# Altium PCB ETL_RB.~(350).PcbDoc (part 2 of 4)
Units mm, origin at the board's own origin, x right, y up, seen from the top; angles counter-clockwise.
Board outline 130.3 x 56.5 mm, 8 copper layers (Top Layer, plane 1, M1, plane 2, plane 3, M2, plane 4, Bottom Layer), stack 0.972 mm thick; 211 components, 188 nets, 1864 pads, 919 vias.
Unrouted connection lines stored in the file: 387.

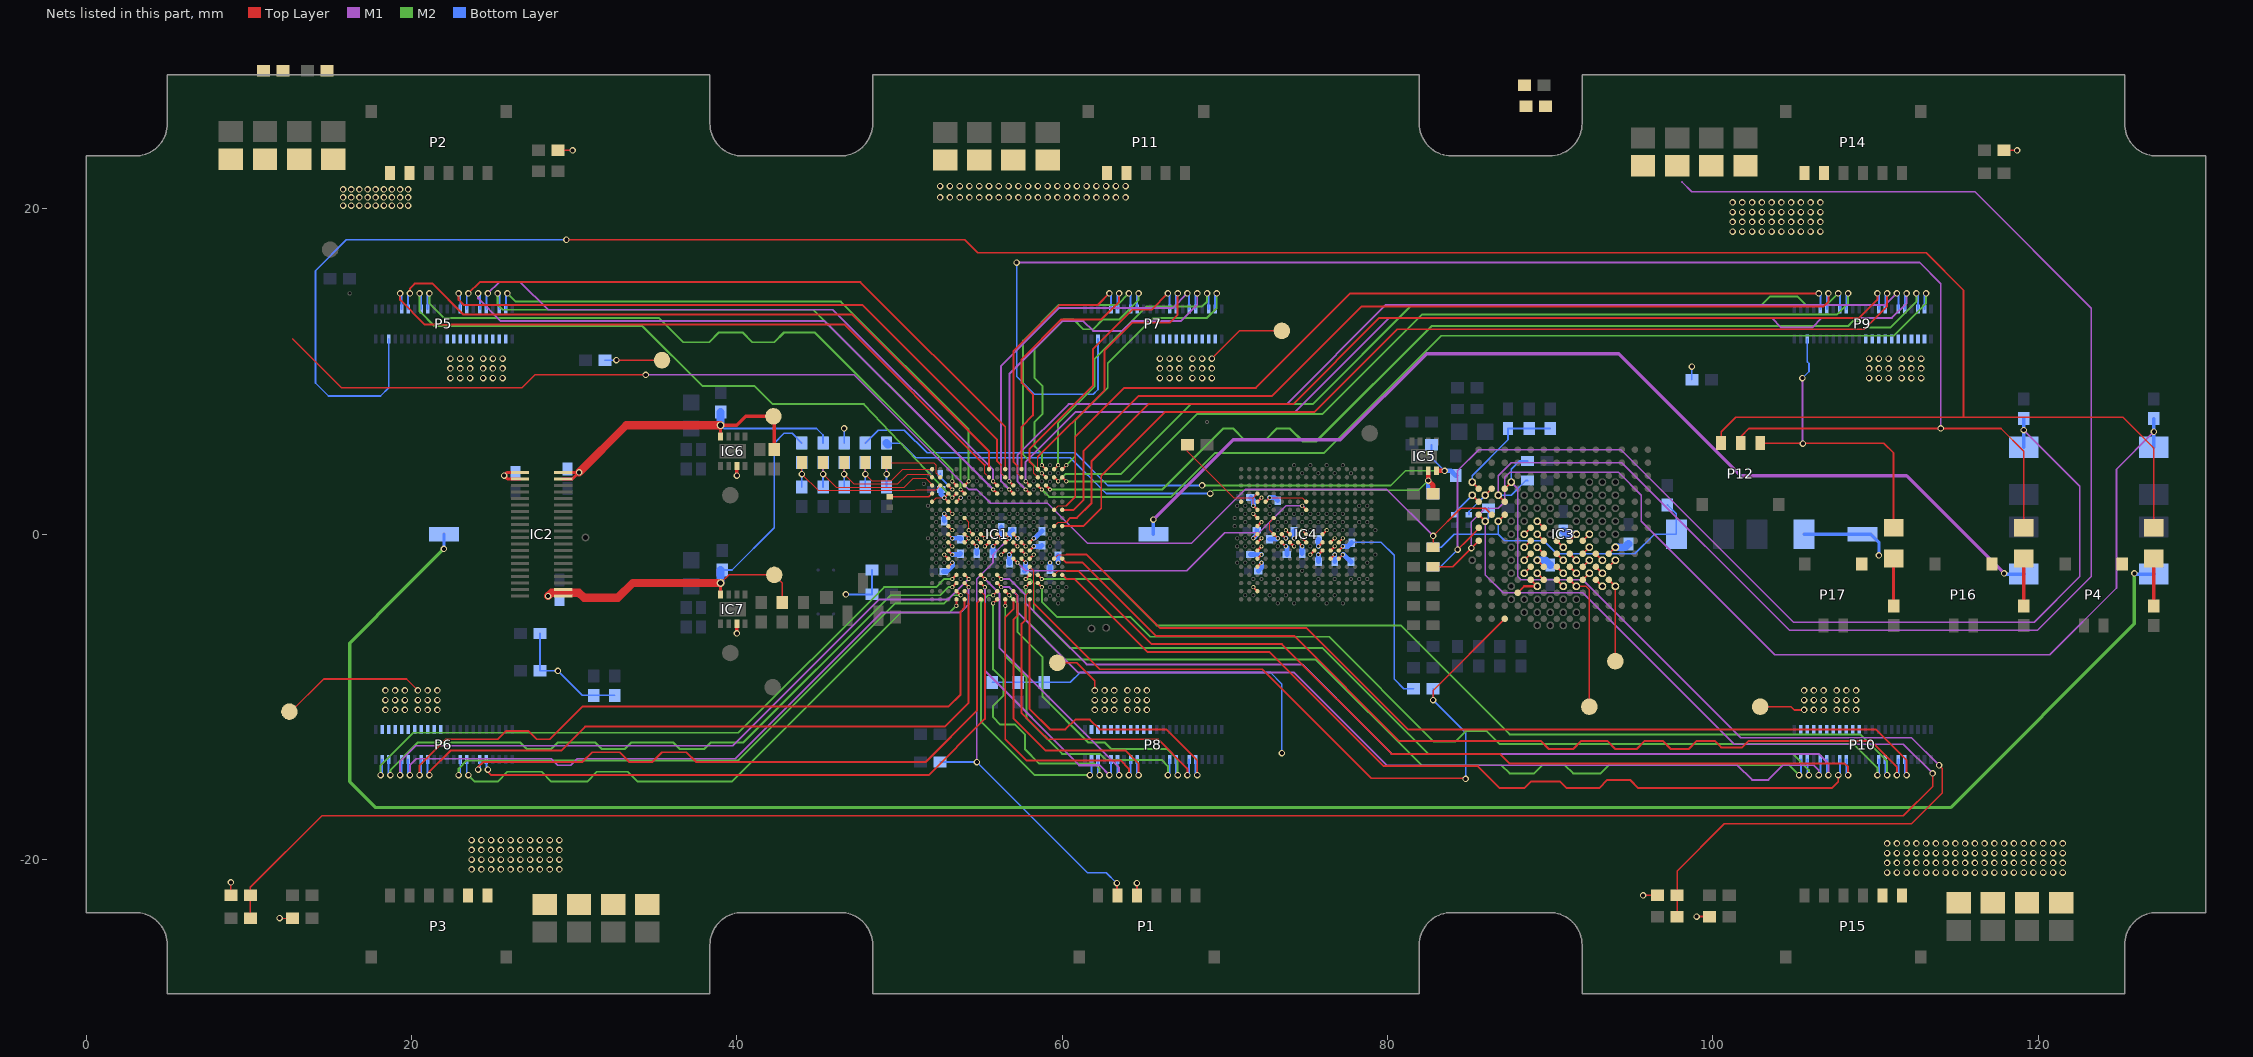
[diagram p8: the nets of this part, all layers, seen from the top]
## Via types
v1: diameter 0.4, hole 0.25, Top Layer to Bottom Layer, 919 vias

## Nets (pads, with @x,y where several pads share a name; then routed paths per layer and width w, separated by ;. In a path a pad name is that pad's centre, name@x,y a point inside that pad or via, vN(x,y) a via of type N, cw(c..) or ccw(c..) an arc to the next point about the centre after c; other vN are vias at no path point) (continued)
1V2_RB: C111.1 C112.1 C113.1 C114.1 C115.1 C116.1 C117.1 C118.1 C119.1 C120.1 C121.1 C122.1 C123.1 C124.1 C125.1 C126.1 C127.1 C128.1 C129.1 C130.1 C131.1 C132.1 C133.1 C134.1 C135.1 C160.1 C162.1 C163.1 C164.1 C165.1 C166.1 C167.1 C168.1 IC1.D3 IC1.E1 IC1.E3 IC1.E4 IC1.F3 IC1.G3 IC1.G5 IC1.H3 IC1.J3 IC1.J5 IC1.J6 IC1.J7 IC1.J8 IC1.J9 IC1.J11 IC1.K3 IC1.K5 IC1.K6 IC1.K7 IC1.K8 IC1.K9 IC1.K11 IC1.K12 IC1.K13 IC1.L3 IC1.L10 IC1.L11 IC1.L12 IC1.L13 IC1.M3 IC1.M12 IC1.M13 IC1.N3 IC2.38 IC2.40 IC4.D3 IC4.E1 IC4.E3 IC4.E4 IC4.E9 IC4.F3 IC4.G3 IC4.G5 IC4.H3 IC4.J3 IC4.J5 IC4.J6 IC4.J7 IC4.J8 IC4.J9 IC4.J11 IC4.K3 IC4.K6 IC4.K7 IC4.K8 IC4.K9 IC4.K11 IC4.K12 IC4.K13 IC4.L3 IC4.L10 IC4.L11 IC4.L12 IC4.L13 IC4.M3 IC4.M12 IC4.M13 IC4.N3 IC4.T3 IC6.3 IC7.3 P1.4 P11.1 P11.2 pad.1@52.75,1.25 pad.1@52.75,2.25 pad.1@52.75,-1.25 pad.1@53.25,0.25 pad.1@53.25,1.25 pad.1@53.25,-0.25 pad.1@53.25,-0.75 pad.1@53.25,-1.25 pad.1@53.25,-1.75 pad.1@53.75,2.25 pad.1@54.25,0.25 pad.1@54.25,-0.25 pad.1@54.75,-0.25 pad.1@54.75,-0.75 pad.1@55.25,-0.25 pad.1@55.25,-0.75 pad.1@55.75,-0.25 pad.1@55.75,-0.75 pad.1@56.25,-0.25 pad.1@56.25,-1.25 pad.1@56.75,-1.25 pad.1@57.25,-0.25 pad.1@57.25,-0.75 pad.1@57.75,-0.75 pad.1@57.75,-1.25 pad.1@57.75,-1.75 pad.1@58.25,-0.25 pad.1@58.25,-0.75 pad.1@58.25,-1.25 pad.1@59.25,-1.75 pad.1@59.75,-1.75 pad.1@71.75,1.25 pad.1@71.75,1.75 pad.1@71.75,-0.25 pad.1@71.75,-3.25 pad.1@72.25,0.75 pad.1@72.25,2.25 pad.1@72.25,-0.25 pad.1@72.25,-0.75 pad.1@72.25,-1.25 pad.1@72.25,-1.75 pad.1@72.75,2.25 pad.1@73.25,-0.25 pad.1@73.75,0.25 pad.1@73.75,-0.25 pad.1@73.75,-0.75 pad.1@74.25,-0.25 pad.1@74.25,-0.75 pad.1@74.75,0.25 pad.1@74.75,-0.25 pad.1@74.75,-0.75 pad.1@75.25,-1.25 pad.1@75.75,-0.75 pad.1@75.75,-1.25 pad.1@76.25,0.25 pad.1@76.75,-0.25 pad.1@76.75,-0.75 pad.1@76.75,-1.25 pad.1@77.25,-0.25 pad.1@77.25,-0.75 pad.1@77.25,-1.25 R101.2 R102.1 R103.2 R104.2 R105.2 R106.2 R107.1 R109.2 R110.2 R121.2 R202.2 R204.2 R206.2 R208.2 R210.2 R237.2 R238.2 R239.2 TP6.1 | length 106.8
  Top Layer w0.076: v1(11.9,-23.6) R204.2@12.7,-23.6 ; IC1.E1@52,2 52.25,2.25 pad.1@52.75,2.25 ; IC1.K5@54,-0.5 pad.1@54.25,-0.25 ; IC1.G5@54,1 54.25,0.75 pad.1@54.25,0.25 ; R238.2@67.7,5.5 67.7,5.1 70.55,2.25 71,2.25 ; IC4.E1@71,2 71,2.25 ; pad.1@71.75,1.75 71.75,2.25 ; IC4.D3@72,2.5 71.75,2.25 ; pad.1@72.75,2.25 74.75,2.25 IC4.E9@75,2 ; IC4.J5@73,0 72.75,0.25 72.75,0.75 IC4.G5@73,1 ; 71,2.25 71.75,2.25
  Top Layer w0.102: R202.2@29,23.6 v1(29.9,23.6) ; v1(32.6,10.7) TP6.1@35.4,10.7 ; pad.1@52.75,2.25 IC1.D3@53,2.5 ; v1(64.586,-21.438) 64.6,-21.452 P1.4@64.6,-22.2 ; v1(99,-23.5) R208.2@99.8,-23.5 ; R206.2@117.9,23.6 v1(118.7,23.6)
  Top Layer w0.13: pad.1@52.75,-1.25 IC1.M3@53,-1.5 ; pad.1@52.75,1.25 IC1.G3@53,1 ; pad.1@52.75,2.25 IC1.E3@53,2 ; IC1.N3@53,-2 pad.1@53.25,-1.75 ; IC1.L3@53,-1 pad.1@53.25,-1.25 ; IC1.K3@53,-0.5 pad.1@53.25,-0.75 ; IC1.J3@53,0 pad.1@53.25,-0.25 ; IC1.H3@53,0.5 pad.1@53.25,0.25 ; IC1.F3@53,1.5 pad.1@53.25,1.25 ; IC1.E4@53.5,2 pad.1@53.75,2.25 ; IC1.J5@54,0 pad.1@54.25,-0.25 ; pad.1@54.25,0.25 IC1.J6@54.5,0 ; IC1.K6@54.5,-0.5 pad.1@54.75,-0.75 ; pad.1@54.75,-0.25 IC1.K7@55,-0.5 ; IC1.J7@55,0 pad.1@55.25,-0.25 ; pad.1@55.25,-0.75 IC1.K8@55.5,-0.5 ; IC1.J8@55.5,0 pad.1@55.75,-0.25 ; pad.1@55.75,-0.75 IC1.K9@56,-0.5 ; IC1.J9@56,0 pad.1@56.25,-0.25 ; pad.1@56.25,-1.25 IC1.L10@56.5,-1 ; pad.1@56.75,-1.25 IC1.L11@57,-1 ; IC1.K11@57,-0.5 pad.1@57.25,-0.75 ; IC1.J11@57,0 pad.1@57.25,-0.25 ; IC1.M12@57.5,-1.5 pad.1@57.75,-1.75 ; IC1.L12@57.5,-1 pad.1@57.75,-1.25 ; IC1.K12@57.5,-0.5 pad.1@57.75,-0.75 ; IC1.M13@58,-1.5 pad.1@58.25,-1.25 ; IC1.L13@58,-1 pad.1@58.25,-0.75 ; IC1.K13@58,-0.5 pad.1@58.25,-0.25 ; pad.1@71.75,-3.25 IC4.T3@72,-3.5 ; pad.1@71.75,-0.25 IC4.J3@72,0 ; pad.1@71.75,1.25 IC4.G3@72,1 ; pad.1@71.75,1.75 IC4.F3@72,1.5 ; IC4.N3@72,-2 pad.1@72.25,-1.75 ; IC4.M3@72,-1.5 pad.1@72.25,-1.25 ; IC4.L3@72,-1 pad.1@72.25,-0.75 ; IC4.K3@72,-0.5 pad.1@72.25,-0.25 ; IC4.H3@72,0.5 pad.1@72.25,0.75 ; IC4.E3@72,2 pad.1@72.25,2.25 ; IC4.E4@72.5,2 pad.1@72.75,2.25 ; IC4.J5@73,0 pad.1@73.25,-0.25 ; IC4.K6@73.5,-0.5 pad.1@73.75,-0.75 ; IC4.J6@73.5,0 pad.1@73.75,-0.25 ; pad.1@73.75,0.25 IC4.J7@74,0 ; IC4.K7@74,-0.5 pad.1@74.25,-0.75 ; pad.1@74.25,-0.25 IC4.J8@74.5,0 ; IC4.K8@74.5,-0.5 pad.1@74.75,-0.75 ; pad.1@74.75,-0.25 IC4.K9@75,-0.5 ; pad.1@74.75,0.25 IC4.J9@75,0 ; pad.1@75.25,-1.25 IC4.L10@75.5,-1 ; pad.1@75.75,-1.25 IC4.L11@76,-1 ; pad.1@75.75,-0.75 IC4.K11@76,-0.5 ; IC4.J11@76,0 pad.1@76.25,0.25 ; IC4.M12@76.5,-1.5 pad.1@76.75,-1.25 ; IC4.L12@76.5,-1 pad.1@76.75,-0.75 ; IC4.K12@76.5,-0.5 pad.1@76.75,-0.25 ; IC4.M13@77,-1.5 pad.1@77.25,-1.25 ; IC4.L13@77,-1 pad.1@77.25,-0.75 ; IC4.K13@77,-0.5 pad.1@77.25,-0.25
  Top Layer w0.2: IC2.38@26.67,3.4 25.9,3.4 v1(25.7,3.6) 25.9,3.8 IC2.40@26.67,3.8 ; v1(40,-6.1) IC7.3@40,-5.5 ; v1(40,3.6) IC6.3@40,4.2
  Bottom Layer w0.076: C133.1@71.56,2.25 C133.1@71.6,2.25
  Bottom Layer w0.102: R104.2@27.9,-6.1 R103.2@27.9,-8.4 v1(29,-8.4) 30.5,-9.9 R105.2@31.2,-9.9 R106.2@32.5,-9.9 ; R239.2@31.9,10.7 v1(32.6,10.7) ; R121.2@46.6,5.6 v1(46.6,6.5) ; R110.2@55.7,-9.1 R109.2@57.3,-9.1 R210.2@58.9,-9.1 60.5,-9.1 61.1,-8.5 72.8,-8.5 73.5,-9.2 v1(73.5,-13.453) ; C166.1@77.8,-0.51 77.81,-0.5 79.6,-0.5 80.4,-1.3 80.4,-8.9 81,-9.5 R107.1@81.6,-9.5 ; R237.2@98.7,9.5 98.7,9.6 v1(98.7,10.3)
  Bottom Layer w0.13: v1(46.7,-3.7) R101.2@48.3,-3.7 R102.1@48.3,-2.2 ; pad.1@71.75,-0.25 pad.1@71.8,-0.2
  Bottom Layer w0.2: pad.1@53.75,2.25 pad.1@53.79,2.25 ; C113.1@59.75,-1.31 59.79,-1.31 C113.1@59.8,-1.3
  Bottom Layer w0.3: C119.1@52.56,2.75 52.56,2.44 pad.1@52.75,2.25 ; C125.1@52.71,-2.3 52.9,-2.3 53.25,-1.95 pad.1@53.25,-1.75 ; C116.1@52.75,0.81 pad.1@52.75,1.25 ; pad.1@53.25,-1.25 53.69,-1.25 C117.1@53.75,-1.19 ; pad.1@53.25,-0.25 53.75,-0.25 C126.1@53.75,-0.31 ; C114.1@54.75,-1.19 pad.1@54.75,-0.75 ; C122.1@55.75,-1.19 pad.1@55.75,-0.75 ; pad.1@56.25,-0.25 C120.1@56.25,0.44 ; C118.1@56.75,-1.79 pad.1@56.75,-1.25 ; C123.1@57.7,-2.25 C123.1@57.69,-2.25 57.75,-2.19 pad.1@57.75,-1.75 ; pad.1@58.25,-0.75 58.69,-0.75 C115.1@58.75,-0.69 ; pad.1@58.25,-0.25 58.31,-0.25 58.409,-0.151 58.416,-0.151 58.651,0.084 58.651,0.091 C124.1@58.75,0.19 ; C121.1@59.25,-2.19 pad.1@59.25,-1.75 ; pad.1@59.75,-1.75 C113.1@59.75,-1.31 ; C130.1@71.56,-1.25 pad.1@72.25,-1.25 ; C133.1@71.6,2.25 71.75,2.1 pad.1@71.75,1.75 ; pad.1@71.8,-0.2 71.96,-0.04 C164.1@71.96,0.25 ; C132.1@72.06,-2.25 72.25,-2.06 pad.1@72.25,-1.75 ; C163.1@72.75,-0.31 73.19,-0.31 pad.1@73.25,-0.25 ; pad.1@72.75,2.25 73.06,2.25 C167.1@73.25,2.06 ; pad.1@73.75,-0.75 73.81,-0.81 C168.1@73.81,-1.25 ; pad.1@74.25,-0.25 C129.1@74.25,0.19 ; C128.1@74.75,-1.19 pad.1@74.75,-0.75 ; C134.1@75.75,-1.69 pad.1@75.75,-1.25 ; pad.1@75.75,-0.75 C131.1@75.75,-0.31 ; C165.1@76.75,-1.69 pad.1@76.75,-1.25 ; pad.1@77.25,-1.25 77.3,-1.25 77.75,-1.7 C135.1@77.75,-1.69 ; pad.1@77.25,-0.75 77.56,-0.75 C166.1@77.8,-0.51
  other v1: 52.5,20.7 53.1,20.7 53.7,20.7 54.3,20.7 54.9,20.7 55.5,20.7 56.1,20.7 56.7,20.7 57.3,20.7 57.9,20.7 58.5,20.7 59.1,20.7 59.7,20.7 60.3,20.7 60.9,20.7 61.5,20.7 62.1,20.7 62.7,20.7 63.3,20.7 63.9,20.7 52.5,21.4 53.1,21.4 53.7,21.4 54.3,21.4 54.9,21.4 55.5,21.4 56.1,21.4 56.7,21.4 57.3,21.4 57.9,21.4 58.5,21.4 59.1,21.4 59.7,21.4 60.3,21.4 60.9,21.4 61.5,21.4 62.1,21.4 62.7,21.4 63.3,21.4 63.9,21.4
1V2A: C218.1 C219.1 C220.1 C221.1 P2.1 P2.2 P5.1 P5.2 P5.3 P5.4 P5.5 P5.6 P5.7 P5.8 P5.9 P5.10 P6.6 P6.7 P6.8 P6.9 P6.10 R214.2 TP1.1 | length 9
  Top Layer w0.102: TP1.1@12.5,-10.9 12.6,-10.9 14.6,-8.9 19.7,-8.9 v1(20.4,-9.6)
  other v1: 20.4,-10.8 21,-10.8 21.6,-10.8 20.4,-10.2 21,-10.2 21.6,-10.2 21,-9.6 21.6,-9.6 22.4,9.6 23,9.6 23.6,9.6 24.4,9.6 25,9.6 25.6,9.6 22.4,10.2 23,10.2 23.6,10.2 24.4,10.2 25,10.2 25.6,10.2 22.4,10.8 23,10.8 23.6,10.8 24.4,10.8 25,10.8 25.6,10.8 15.8,20.2 16.3,20.2 16.8,20.2 17.3,20.2 17.8,20.2 18.3,20.2 18.8,20.2 19.3,20.2 19.8,20.2 15.8,20.7 16.3,20.7 16.8,20.7 17.3,20.7 17.8,20.7 18.3,20.7 18.8,20.7 19.3,20.7 19.8,20.7 15.8,21.2 16.3,21.2 16.8,21.2 17.3,21.2 17.8,21.2 18.3,21.2 18.8,21.2 19.3,21.2 19.8,21.2
1V2B: C222.1 C224.1 C225.1 Cc223.1 P3.1 P3.2 P6.1 P6.2 P6.3 P6.4 P6.5 P8.1 P8.2 P8.3 P8.4 P8.5 P8.6 P8.7 P8.8 P8.9 P8.10 R216.2 TP2.1 | length 4.2
  Top Layer w0.102: R216.2@8.9,-22.2 v1(8.9,-21.4) ; TP2.1@59.7,-7.9 60.9,-7.9 62,-9 v1(62,-9.6)
  other v1: 23.7,-20.6 24.3,-20.6 24.9,-20.6 25.5,-20.6 26.1,-20.6 26.7,-20.6 27.3,-20.6 27.9,-20.6 28.5,-20.6 29.1,-20.6 23.7,-20 24.3,-20 24.9,-20 25.5,-20 26.1,-20 26.7,-20 27.3,-20 27.9,-20 28.5,-20 29.1,-20 23.7,-19.4 24.3,-19.4 24.9,-19.4 25.5,-19.4 26.1,-19.4 26.7,-19.4 27.3,-19.4 27.9,-19.4 28.5,-19.4 29.1,-19.4 23.7,-18.8 24.3,-18.8 24.9,-18.8 25.5,-18.8 26.1,-18.8 26.7,-18.8 27.3,-18.8 27.9,-18.8 28.5,-18.8 29.1,-18.8 18.4,-10.8 19,-10.8 19.6,-10.8 62,-10.8 62.6,-10.8 63.2,-10.8 64,-10.8 64.6,-10.8 65.2,-10.8 18.4,-10.2 19,-10.2 19.6,-10.2 62,-10.2 62.6,-10.2 63.2,-10.2 64,-10.2 64.6,-10.2 65.2,-10.2 18.4,-9.6 19,-9.6 19.6,-9.6 62.6,-9.6 63.2,-9.6 64,-9.6 64.6,-9.6 65.2,-9.6
1V2C: C226.1 C227.1 C228.1 C229.1 P7.1 P7.2 P7.3 P7.4 P7.5 P7.6 P7.7 P7.8 P7.9 P7.10 P9.1 P9.2 P9.3 P9.4 P9.5 P14.1 P14.2 R218.2 TP3.1 | length 5
  Top Layer w0.102: v1(69.2,10.8) 70.9,12.5 TP3.1@73.5,12.5
  other v1: 66,9.6 66.6,9.6 67.2,9.6 68,9.6 68.6,9.6 69.2,9.6 111.6,9.6 112.2,9.6 112.8,9.6 66,10.2 66.6,10.2 67.2,10.2 68,10.2 68.6,10.2 69.2,10.2 111.6,10.2 112.2,10.2 112.8,10.2 66,10.8 66.6,10.8 67.2,10.8 68,10.8 68.6,10.8 111.6,10.8 112.2,10.8 112.8,10.8 101.2,18.6 101.8,18.6 102.4,18.6 103,18.6 103.6,18.6 104.2,18.6 104.8,18.6 105.4,18.6 106,18.6 106.6,18.6 101.2,19.2 101.8,19.2 102.4,19.2 103,19.2 103.6,19.2 104.2,19.2 104.8,19.2 105.4,19.2 106,19.2 106.6,19.2 101.2,19.8 101.8,19.8 102.4,19.8 103,19.8 103.6,19.8 104.2,19.8 104.8,19.8 105.4,19.8 106,19.8 106.6,19.8 101.2,20.4 101.8,20.4 102.4,20.4 103,20.4 103.6,20.4 104.2,20.4 104.8,20.4 105.4,20.4 106,20.4 106.6,20.4
1V2D: C230.1 C231.1 C232.1 C233.1 P9.6 P9.7 P9.8 P9.9 P9.10 P10.1 P10.2 P10.3 P10.4 P10.5 P10.6 P10.7 P10.8 P10.9 P10.10 P15.1 P15.2 R220.2 TP4.1 | length 3.7
  Top Layer w0.102: v1(95.7,-22.2) R220.2@96.6,-22.2 ; TP4.1@102.9,-10.6 104.8,-10.6 105,-10.8 v1(105.6,-10.8)
  other v1: 110.7,-20.8 111.3,-20.8 111.9,-20.8 112.5,-20.8 113.1,-20.8 113.7,-20.8 114.3,-20.8 114.9,-20.8 115.5,-20.8 116.1,-20.8 116.7,-20.8 117.3,-20.8 117.9,-20.8 118.5,-20.8 119.1,-20.8 119.7,-20.8 120.3,-20.8 120.9,-20.8 121.5,-20.8 110.7,-20.2 111.3,-20.2 111.9,-20.2 112.5,-20.2 113.1,-20.2 113.7,-20.2 114.3,-20.2 114.9,-20.2 115.5,-20.2 116.1,-20.2 116.7,-20.2 117.3,-20.2 117.9,-20.2 118.5,-20.2 119.1,-20.2 119.7,-20.2 120.3,-20.2 120.9,-20.2 121.5,-20.2 110.7,-19.6 111.3,-19.6 111.9,-19.6 112.5,-19.6 113.1,-19.6 113.7,-19.6 114.3,-19.6 114.9,-19.6 115.5,-19.6 116.1,-19.6 116.7,-19.6 117.3,-19.6 117.9,-19.6 118.5,-19.6 119.1,-19.6 119.7,-19.6 120.3,-19.6 120.9,-19.6 121.5,-19.6 110.7,-19 111.3,-19 111.9,-19 112.5,-19 113.1,-19 113.7,-19 114.3,-19 114.9,-19 115.5,-19 116.1,-19 116.7,-19 117.3,-19 117.9,-19 118.5,-19 119.1,-19 119.7,-19 120.3,-19 120.9,-19 121.5,-19 106.2,-10.8 106.8,-10.8 107.6,-10.8 108.2,-10.8 108.8,-10.8 105.6,-10.2 106.2,-10.2 106.8,-10.2 107.6,-10.2 108.2,-10.2 108.8,-10.2 105.6,-9.6 106.2,-9.6 106.8,-9.6 107.6,-9.6 108.2,-9.6 108.8,-9.6 109.6,9.6 110.2,9.6 110.8,9.6 109.6,10.2 110.2,10.2 110.8,10.2 109.6,10.8 110.2,10.8 110.8,10.8
1V5A: C138.1 C139.1 IC3.D9 IC3.D10 IC3.D11 IC3.E9 IC3.E10 IC3.E11 IC3.F8 IC3.F9 IC3.F10 IC3.F11 IC3.J7 IC3.J8 IC3.J9 IC3.J10 IC3.J11 IC3.K7 IC3.K8 IC3.K9 IC3.K10 IC3.K11 IC3.L12 IC5.7 pad.1@88.4,0 pad.1@88.4,-0.8 pad.1@88.4,-1.6 pad.1@88.4,-2.4 pad.1@89.2,0 pad.1@89.2,0.8 pad.1@89.2,-0.8 pad.1@89.2,-1.6 pad.1@89.2,-2.4 pad.1@89.2,-3.2 pad.1@92.4,0 pad.1@92.4,-0.8 pad.1@92.4,-1.6 pad.1@92.4,-2.4 pad.1@93.2,-1.6 pad.1@93.2,-2.4 pad.1@93.2,-3.2 pad.1@94,-0.8 pad.1@94,-1.6 pad.1@94,-3.2 R113.1 R128.1 R133.2 TP7.1 | length 56.8
  Top Layer w0.102: TP7.1@94,-7.8 pad.1@94,-3.2
  Top Layer w0.13: IC3.L12@88,-3.6 88.4,-3.2 pad.1@89.2,-3.2 IC3.K11@88.8,-2.8 ; pad.1@88.4,-2.4 IC3.K10@88.8,-2 ; pad.1@88.4,-1.6 IC3.K9@88.8,-1.2 ; pad.1@88.4,-0.8 IC3.K8@88.8,-0.4 ; pad.1@88.4,0 IC3.K7@88.8,0.4 ; pad.1@89.2,-2.4 IC3.J11@89.6,-2.8 ; pad.1@89.2,-1.6 IC3.J10@89.6,-2 ; pad.1@89.2,-0.8 IC3.J9@89.6,-1.2 ; pad.1@89.2,0 IC3.J8@89.6,-0.4 ; pad.1@89.2,0.8 IC3.J7@89.6,0.4 ; IC3.F11@92,-2.8 pad.1@92.4,-2.4 ; IC3.F10@92,-2 pad.1@92.4,-1.6 ; IC3.F9@92,-1.2 pad.1@92.4,-0.8 ; IC3.F8@92,-0.4 pad.1@92.4,0 ; IC3.E11@92.8,-2.8 pad.1@93.2,-3.2 ; IC3.E10@92.8,-2 pad.1@93.2,-2.4 ; IC3.E9@92.8,-1.2 pad.1@93.2,-1.6 ; IC3.D11@93.6,-2.8 pad.1@94,-3.2 ; IC3.D10@93.6,-2 pad.1@94,-1.6 ; IC3.D9@93.6,-1.2 pad.1@94,-0.8
  Top Layer w0.3: IC5.7@82.5,3.9 v1(82.5,3.3) 82.8,3 R113.1@82.8,2.5 R113.1@82.9,2.6
  M2 w0.102: v1(69.1,2.5) 69.3,2.7 81.9,2.7 v1(82.5,3.3)
  Bottom Layer w0.102: R133.2@49.3,5.5 49.4,5.6 50.1,5.6 51,4.7 60.5,4.7 62.7,2.5 v1(69.1,2.5)
  Bottom Layer w0.3: v1(82.5,3.3) 82.5,2.8 R128.1@82.8,2.5 R128.1@82.9,2.6
  Bottom Layer w0.48: R133.2@49.2,5.6 R133.2@49.3,5.5 ; pad.1@89.2,-1.6 89.7,-1.6 C138.1@90,-1.9 ; pad.1@94,-0.8 94.6,-0.8 C139.1@94.8,-0.6
1V5D: C140.1 IC3.G8 IC3.G9 IC3.G10 IC3.G11 IC3.H8 IC3.H9 IC3.H10 IC3.H11 IC5.8 pad.1@90.8,-0.8 pad.1@90.8,-1.6 pad.1@90.8,-2.4 pad.1@90.8,-3.2 pad.1@91.6,0 pad.1@91.6,-1.6 pad.1@91.6,-2.4 pad.1@91.6,-3.2 R111.1 R117.2 R127.1 TP8.1 | length 54.5
  Top Layer w0.102: pad.1@91.6,-3.2 92.2,-3.2 92.4,-3.4 TP8.1@92.4,-10.6
  Top Layer w0.13: IC3.H11@90.4,-2.8 pad.1@90.8,-3.2 ; IC3.H10@90.4,-2 pad.1@90.8,-2.4 ; IC3.H9@90.4,-1.2 pad.1@90.8,-1.6 ; IC3.H8@90.4,-0.4 pad.1@90.8,-0.8 ; IC3.G11@91.2,-2.8 pad.1@91.6,-3.2 ; IC3.G10@91.2,-2 pad.1@91.6,-2.4 ; IC3.G9@91.2,-1.2 pad.1@91.6,-1.6 ; IC3.G8@91.2,-0.4 pad.1@91.6,0
  Top Layer w0.3: IC5.8@83,3.9 v1(83.5,3.9)
  M2 w0.102: v1(68.6,3) 80.2,3 81.1,3.9 v1(83.5,3.9)
  Bottom Layer w0.102: R117.2@47.9,5.6 48.7,6.4 50.3,6.4 51.7,5 60.8,5 62.8,3 v1(68.6,3) ; R127.1@82.7,5.5 82.7,4.7 v1(83.5,3.9)
  Bottom Layer w0.3: v1(83.5,3.9) 83.9,3.9 R111.1@84.2,3.6
  Bottom Layer w0.48: C140.1@90.8,0.2 91,0 pad.1@91.6,0
2V5F: C136.1 IC1.J10 IC1.K10 P1.5 pad.1@56.75,-0.25 R132.1 | length 30.6
  Top Layer w0.102: v1(63.366,-21.438) 63.366,-22.166 P1.5@63.4,-22.2
  Top Layer w0.13: IC1.K10@56.5,-0.5 pad.1@56.75,-0.25 IC1.J10@56.5,0
  M1 w0.102: v1(54.75,-14) 54.75,-2.75 55.75,-1.75 55.75,-1.25 pad.1@56.75,-0.25
  Bottom Layer w0.102: R132.1@52.5,-14 v1(54.75,-14) 61.55,-20.8 62.7,-20.8 63.338,-21.438 v1(63.366,-21.438)
  Bottom Layer w0.3: pad.1@56.75,-0.25 56.75,0.06 C136.1@56.94,0.25
2V5RX: C154.1 IC2.1 IC2.3 IC7.8 pad.1@39,-3 R124.1 R125.2 R135.2 TP9.1 | length 29.8
  Top Layer w0.102: pad.1@39,-3 39.5,-2.5 TP9.1@42.3,-2.5 42.8,-3 R124.1@42.8,-4.2
  Top Layer w0.2: IC7.8@39,-3.7 pad.1@39,-3
  Top Layer w0.5: v1(28.4,-3.8) 28.6,-3.6 30.3,-3.6 30.6,-3.9 32.7,-3.9 33.6,-3 pad.1@39,-3
  Bottom Layer w0.102: R125.2@39.1,-2.2 39.7,-2.2 42.3,0.4 42.3,5.6 42.9,6.2 43.4,6.2 R135.2@44,5.6
  Bottom Layer w0.5: pad.1@39,-3 R125.2@39,-2.2
2V5TX: C153.1 IC2.37 IC2.39 IC6.8 pad.1@39,6.7 R114.2 R116.1 R119.2 TP10.1 | length 26.1
  Top Layer w0.2: IC2.37@29.33,3.4 29.9,3.4 v1(30.3,3.8) IC2.39@29.33,3.8 ; IC6.8@39,6 pad.1@39,6.7 40,6.7 40.55,7.25 TP10.1@42.25,7.25 42.3,7.2 R116.1@42.3,5.2
  Top Layer w0.5: v1(30.3,3.8) 33.2,6.7 pad.1@39,6.7
  Bottom Layer w0.102: pad.1@39,6.7 39.2,6.5 44.9,6.5 45.3,6.1 R119.2@45.3,5.6
  Bottom Layer w0.5: pad.1@39,6.7 R114.2@39,7.5
ADC1: C109.1 IC1.A1 R117.1 R118.2 | length 6.8
  Top Layer w0.076: C109.1@47.9,4.4 v1(47.9,3.7) 48.3,3.3 49.5,3.3 50.2,4 IC1.A1@52,4
  Bottom Layer w0.102: R118.2@47.9,2.9 v1(47.9,3.7) R117.1@47.9,4.4
ADC2: C141.1 IC1.B2 R133.1 R134.2 | length 6.2
  Top Layer w0.076: v1(49.2,3.7) C141.1@49.2,4.4 52.1,4.4 52.25,4.25 52.25,3.75 IC1.B2@52.5,3.5
  Bottom Layer w0.102: R134.2@49.2,2.9 v1(49.2,3.7) R133.1@49.2,4.4
ADC3: C142.1 IC1.B1 R121.1 R136.2 | length 8.2
  Top Layer w0.076: C142.1@46.6,4.4 v1(46.6,3.7) 47.2,3.1 49.9,3.1 50.5,3.7 51.8,3.7 IC1.B1@52,3.5
  Bottom Layer w0.102: R136.2@46.6,2.9 v1(46.6,3.7) R121.1@46.6,4.4
ADC4: IC1.C3 pad.1@53.25,2.75 R144.2 | length 1.7
  Top Layer w0.13: IC1.C3@53,3 pad.1@53.25,2.75
  Bottom Layer w0.102: R144.2@52.5,3.75 52.5,3.5 pad.1@53.25,2.75
ADC5: C151.1 IC1.C2 R122.2 R135.1 | length 11.2
  Top Layer w0.076: C151.1@44,4.4 v1(44,3.7) 45,2.7 50.95,2.7 51,2.75 52.25,2.75 ; 52.25,2.75 IC1.C2@52.5,3
  Bottom Layer w0.102: R122.2@44,2.9 v1(44,3.7) R135.1@44,4.4
ADC6: C150.1 IC1.C1 R119.1 R120.2 | length 9.6
  Top Layer w0.076: C150.1@45.3,4.4 v1(45.3,3.7) 46.1,2.9 50.3,2.9 50.85,3.45 51.6,3.45 IC1.C1@52,3.05
  Bottom Layer w0.102: R120.2@45.3,2.9 v1(45.3,3.7) R119.1@45.3,4.4
ADC7: IC1.D1 RT1.2 | length 2.7
  Top Layer w0.102: RT1.2@49.4,2.3 51.8,2.3 IC1.D1@52,2.5
ADC_IN18: C207.2 IC3.P8 R222.1 R223.2 | length 66.4
  Top Layer w0.102: C207.2@82.8,-2 84,-2 IC3.P8@85.6,-0.4
  M1 w0.102: v1(85.15,-0.85) 85.15,0.75 86,1.6 86.8,1.6 87.2,2 87.2,3.5 87.5,3.8 94.2,3.8 95.6,2.4 95.6,0.8 103.8,-7.4 120.7,-7.4 124.8,-3.3 124.8,4 v1(127.1,6.3)
  Bottom Layer w0.203: R222.1@127.1,5.35 R223.2@127.1,7.1
ADC_IN21: C208.2 IC3.P7 R224.1 R225.2 | length 65.2
  Top Layer w0.102: v1(84.3,-0.95) 84.95,-0.3 85.6,0.35 IC3.P7@85.6,0.4
  M1 w0.102: v1(84.3,-0.95) 84.3,3.9 85.6,5.2 94.35,5.2 104.95,-5.4 119.75,-5.4 122.55,-2.6 122.55,2.95 v1(119.1,6.4)
  Bottom Layer w0.102: C208.2@82.8,-2 83.25,-2 v1(84.3,-0.95)
  Bottom Layer w0.203: R224.1@119.1,5.35 R225.2@119.1,7.1
ADC_IN22: C209.2 IC3.M6 pad.1@86.8,0.8 R226.1 R227.2 | length 19.7
  Top Layer w0.13: pad.1@86.8,0.8 IC3.M6@87.2,1.2
  Bottom Layer w0.102: C209.2@82.8,-0.8 83.3,-0.8 84.1,0 86.8,0 ; pad.1@86.8,0.8 86.8,0 ; R227.2@97.2,1.8 97.75,1.25 R226.1@97.75,0 96.4,0 95.2,-1.2 90.4,-1.2 89.6,-0.4 87.2,-0.4 86.8,0
ADC_IN23: C210.2 IC3.N6 R214.1 R215.2 | length 83.7
  Top Layer w0.102: 12.7,12 15.7,9 26.8,9 27.6,9.8 v1(34.4,9.8) ; C210.2@82.8,-0.8 v1(82.8,-0.1) ; v1@82.819,-0.081 84.5,1.6 86,1.6 IC3.N6@86.4,1.2
  M1 w0.102: v1(34.4,9.8) 47.2,9.8 54.25,2.75 54.75,2.75 55.6,1.9 59.1,1.9 61.55,-0.55 67.95,-0.55 71.25,2.75 79.95,2.75 v1(82.8,-0.1)
ADC_IN24: C211.2 IC3.P6 pad.1@86,0.8 R216.1 R217.2 | length 146
  Top Layer w0.102: R217.2@10.1,-23.6 10.1,-21.7 14.5,-17.3 111.7,-17.3 113.5,-15.5 v1(113.5,-14.7)
  Top Layer w0.13: IC3.P6@85.6,1.2 pad.1@86,0.8
  M1 w0.102: pad.1@86,0.8 86,-2.5 87.1,-3.6 92,-3.6 101.3,-12.9 111.7,-12.9 v1(113.5,-14.7)
  Bottom Layer w0.102: pad.1@86,0.8 86.2,1 C211.2@86.2,1.6
ADC_IN25: C212.2 IC3.M5 pad.1@86.8,2.4 R218.1 R219.2 | length 91.2
  Top Layer w0.13: pad.1@86.8,2.4 IC3.M5@87.2,2
  M1 w0.102: pad.1@86.8,2.4 86.8,3.6 87.6,4.4 94.4,4.4 104.7,-5.9 119.95,-5.9 123.25,-2.6 123.25,13.9 116.1,21.05 98.7,21.05 98.1,21.65
  Bottom Layer w0.102: pad.1@86.8,2.4 87.6,2.4 88.5,3.3 C212.2@88.6,3.3
ADC_IN27: IC3.P5 pad.1@85.2,2.4 R243.2 | length 2.2
  Top Layer w0.13: pad.1@85.2,2.4 IC3.P5@85.6,2
  Bottom Layer w0.102: R243.2@84.1,1.2 84.1,1.3 pad.1@85.2,2.4
ADC_IN28: C213.2 IC3.M4 pad.1@87.6,3.2 R220.1 R221.2 | length 62.1
  Top Layer w0.102: R221.2@97.8,-23.5 R220.1@97.8,-22.2 97.8,-20.7 100.7,-17.8 112.2,-17.8 114.1,-15.9 114.1,-14.4 v1(113.9,-14.2)
  Top Layer w0.13: IC3.M4@87.2,2.8 pad.1@87.6,3.2
  M1 w0.102: pad.1@87.6,3.2 88,2.8 88,-2.6 88.2,-2.8 92,-2.8 101.7,-12.5 112.2,-12.5 v1(113.9,-14.2)
  Bottom Layer w0.102: pad.1@87.6,3.2 87.6,4 88.1,4.5 C213.2@88.6,4.5
ADC_IN29: IC3.N4 pad.1@86,2.4 RT2.2 | length 2.2
  Top Layer w0.13: pad.1@86,2.4 IC3.N4@86.4,2.8
  Bottom Layer w0.102: RT2.2@85,1.2 85,1.4 pad.1@86,2.4
ADC_IN30: C214.2 IC3.P4 pad.1@85.2,3.2 R228.1 R229.2 | length 7.4
  Top Layer w0.13: pad.1@85.2,3.2 IC3.P4@85.6,2.8
  Bottom Layer w0.102: pad.1@85.2,3.2 85.2,3.6 87.4,5.8 C214.2@87.4,6.5 R228.1@90,6.5
ADR1_IC4: IC1.M11 IC4.F9 pad.1@57.25,-1.75 pad.1@74.75,1.75 | length 20.2
  Top Layer w0.13: IC1.M11@57,-1.5 pad.1@57.25,-1.75 ; pad.1@74.75,1.75 IC4.F9@75,1.5
  M1 w0.102: pad.1@57.25,-1.75 57.75,-2.25 67.65,-2.25 70,0.1 72.1,0.1 73.75,1.75 pad.1@74.75,1.75
  M1 w0.13: pad.1@74.75,1.75 74.8,1.75 pad.1@74.85,1.7
AGND0: C215.2 P5.19 P12.3 | length 159.5
  Top Layer w0.102: v1(29.53,18.1) 54,18.1 54.8,17.3 113.1,17.3 115.4,15 115.4,7.2 ; P12.3@100.5,5.6 100.5,6.3 101.4,7.2 115.4,7.2 ; C215.2@127.1,0.4 127.1,5.3 125.2,7.2 115.4,7.2
  Bottom Layer w0.102: P5.19@18.6,12 18.6,9 18.1,8.5 14.9,8.5 14.1,9.3 14.1,16.2 16,18.1 v1(29.53,18.1)
AGND1: C216.2 P7.19 P12.2 | length 105.2
  Top Layer w0.102: P12.2@101.7,5.6 101.7,6 102.2,6.5 v1(114,6.5) 117.7,6.5 119.1,5.1 C216.2@119.1,0.4
  M1 w0.102: v1(57.2,16.7) 112.7,16.7 114,15.4 v1(114,6.5)
  Bottom Layer w0.102: v1(57.2,16.7) 57.2,9.7 58.3,8.6 61.9,8.6 62.2,8.9 P7.19@62.2,12
AGND2: C217.2 P9.19 P12.1 | length 19.7
  Top Layer w0.102: P12.1@102.9,5.6 105.5,5.6 110.5,5.6 111.1,5 C217.2@111.1,0.4 ; v1(105.531,5.569) v1@105.531,5.6
  M1 w0.102: v1(105.5,9.6) 105.5,5.6 v1(105.531,5.569)
  Bottom Layer w0.102: v1(105.5,9.6) 105.9,10 105.9,10.5 105.8,10.6 P9.19@105.8,12
BV0: C215.1 CT1.1 P4.3 R230.1 R240.2 | length 139.9
  Top Layer w0.203: R230.1@127.1,-4.4 C215.1@127.1,-1.5
  M2 w0.203: v1(22,-0.9) 19.6,-3.3 16.2,-6.7 16.2,-15.2 17.8,-16.8 114.6,-16.8 125.9,-5.5 v1(125.9,-2.4)
  Bottom Layer w0.203: v1(22,-0.9) CT1.1@22,0 ; v1(125.9,-2.4) 125.95,-2.45 R240.2@127.1,-2.45
BV1: C216.1 CT2.1 P16.3 R231.1 R241.2 | length 67.1
  Top Layer w0.203: R231.1@119.1,-4.4 C216.1@119.1,-1.5
  M1 w0.203: v1(65.6,0.9) 70.5,5.8 77.1,5.8 82.4,11.1 94.2,11.1 101.7,3.6 111.9,3.6 v1(117.9,-2.4)
  Bottom Layer w0.203: CT2.1@65.6,0 v1(65.6,0.9) ; v1(117.9,-2.4) 117.95,-2.45 R241.2@119.1,-2.45
BV2: C217.1 CT3.1 P17.3 R232.1 R242.2 | length 8.6
  Top Layer w0.203: R232.1@111.1,-4.4 C217.1@111.1,-1.5
  Bottom Layer w0.076: v1@110.2,-1.4 v1(110.2,-1.3)
  Bottom Layer w0.203: R242.2@105.6,0 CT3.1@109.2,0 109.7,0 110.2,-0.5 v1(110.2,-1.3)
ECLK0N: IC1.U4 P6.27 pad.1@53.5,-4.4 | length 37
  Top Layer w0.13: pad.1@53.5,-4.4 IC1.U4@53.5,-4
  M2 w0.12: v1(23.5,-14.8) 23.9,-15.2 25.3,-15.2 25.9,-14.6 28,-14.6 28.6,-15.2 30.8,-15.2 31.4,-14.6 33.3,-14.6 33.9,-15.2 39.7,-15.2 50.1,-4.8 53.1,-4.8 pad.1@53.5,-4.4
  Bottom Layer w0.12: P6.27@23.4,-13.85 23.4,-14.7 v1(23.5,-14.8)
ECLK0P: IC1.T4 P6.28 pad.1@53.75,-3.75 | length 37
  Top Layer w0.13: IC1.T4@53.5,-3.5 pad.1@53.75,-3.75
  M2 w0.12: v1(22.9,-14.8) 22.9,-14.4 23.4,-13.9 40.1,-13.9 49.75,-4.25 52.75,-4.25 53.25,-3.75 pad.1@53.75,-3.75
  Bottom Layer w0.12: v1(22.9,-14.8) 23,-14.7 P6.28@23,-13.85
ECLK1N: IC1.R4 P6.39 pad.1@53.25,-3.25 | length 41.8
  Top Layer w0.13: pad.1@53.25,-3.25 IC1.R4@53.5,-3
  M2 w0.12: v1(18.7,-14.8) 18.7,-14.5 20.4,-12.8 26.7,-12.8 27.1,-13.2 28.6,-13.2 29,-12.8 31.3,-12.8 31.7,-13.2 33.1,-13.2 33.5,-12.8 36.1,-12.8 36.5,-13.2 38,-13.2 38.4,-12.8 40.4,-12.8 49.45,-3.75 52.5,-3.75 53,-3.25 pad.1@53.25,-3.25
  Bottom Layer w0.12: P6.39@18.6,-13.85 18.6,-14.7 v1(18.7,-14.8)
ECLK1P: IC1.P4 P6.40 pad.1@53.25,-2.75 | length 41.8
  Top Layer w0.13: pad.1@53.25,-2.75 IC1.P4@53.5,-2.5
  M2 w0.12: v1(18.1,-14.8) 18.1,-14.2 20.1,-12.2 40.1,-12.2 49.05,-3.25 52.25,-3.25 52.75,-2.75 ; 52.75,-2.75 pad.1@53.25,-2.75
  Bottom Layer w0.12: v1(18.1,-14.8) 18.2,-14.7 P6.40@18.2,-13.85
ECLK2N: IC1.U9 P8.39 pad.1@55.75,-4.25 | length 17.7
  Top Layer w0.13: pad.1@55.75,-4.25 IC1.U9@56,-4
  M2 w0.12: pad.1@55.75,-4.25 55.75,-8.3 56.4,-8.95 56.4,-9.9 55.75,-10.55 55.75,-11.25 56.2,-11.7 57.1,-11.7 57.7,-12.3 57.7,-13.2 58.6,-14.1 62,-14.1 62.3,-14.4 v1(62.3,-14.8)
  Bottom Layer w0.12: P8.39@62.2,-13.85 62.2,-14.7 v1(62.3,-14.8)
ECLK2P: IC1.T9 P8.40 pad.1@55.75,-3.75 | length 17.6
  Top Layer w0.13: pad.1@55.75,-3.75 IC1.T9@56,-3.5
  M2 w0.12: pad.1@55.75,-3.75 55.45,-3.75 55,-4.2 55,-11.5 58.3,-14.8 v1(61.7,-14.8)
  Bottom Layer w0.12: v1(61.7,-14.8) 61.8,-14.7 P8.40@61.8,-13.85
ECLK3N: IC1.U10 P8.28 pad.1@56.5,-4.4 | length 19.3
  Top Layer w0.13: pad.1@56.5,-4.4 IC1.U10@56.5,-4
  M2 w0.12: pad.1@56.5,-4.4 56.5,-7.5 57.8,-8.8 57.8,-11.3 60,-13.5 62.3,-13.5 62.675,-13.875 66.125,-13.875 66.5,-14.25 v1(66.5,-14.8)
  Bottom Layer w0.12: v1(66.5,-14.8) 66.6,-14.7 P8.28@66.6,-13.85
ECLK3P: IC1.T10 P8.27 pad.1@56.75,-3.75 | length 19.3
  Top Layer w0.13: IC1.T10@56.5,-3.5 pad.1@56.75,-3.75
  M2 w0.12: pad.1@56.75,-3.75 57.25,-4.25 57.25,-6 58.8,-7.55 58.8,-10 61.6,-12.8 62.6,-12.8 63,-13.2 66.45,-13.2 67.1,-13.85 v1(67.1,-14.8)
  Bottom Layer w0.12: P8.27@67,-13.85 67,-14.7 v1(67.1,-14.8)
ECLK4N: IC1.R13 P10.40 pad.1@57.75,-3.25 | length 55.7
  Top Layer w0.13: pad.1@57.75,-3.25 IC1.R13@58,-3
  M2 w0.12: pad.1@57.75,-3.25 57.75,-5.25 60.2,-7.7 75.6,-7.7 82.1,-14.2 87,-14.2 87.5,-14.7 89,-14.7 89.5,-14.2 90.9,-14.2 91.4,-14.7 93.1,-14.7 93.6,-14.2 104.7,-14.2 v1(105.3,-14.8)
  Bottom Layer w0.12: v1(105.3,-14.8) 105.4,-14.7 P10.40@105.4,-13.85
ECLK4P: IC1.P13 P10.39 pad.1@57.75,-2.75 | length 55.7
  Top Layer w0.13: pad.1@57.75,-2.75 IC1.P13@58,-2.5
  M2 w0.12: pad.1@57.75,-2.75 58,-2.75 58.25,-3 58.25,-4.75 60.5,-7 76,-7 82.5,-13.5 104.9,-13.5 105.9,-14.5 v1(105.9,-14.8)
  Bottom Layer w0.12: P10.39@105.8,-13.85 105.8,-14.7 v1(105.9,-14.8)
ECLK5N: IC1.R14 P10.28 pad.1@58.75,-3.25 | length 58.8
  Top Layer w0.13: IC1.R14@58.5,-3 pad.1@58.75,-3.25
  M2 w0.12: pad.1@58.75,-3.25 58.75,-4.15 59.7,-5.1 64.2,-5.1 65.4,-6.3 76.4,-6.3 82.85,-12.75 84.15,-12.75 84.8,-12.1 86.1,-12.1 86.9,-12.9 108.65,-12.9 110.1,-14.35 v1(110.1,-14.8)
  Bottom Layer w0.12: v1(110.1,-14.8) 110.2,-14.7 P10.28@110.2,-13.85
ECLK5P: IC1.P14 P10.27 pad.1@58.75,-2.75 | length 58.8
  Top Layer w0.13: IC1.P14@58.5,-2.5 pad.1@58.75,-2.75
  M2 w0.12: pad.1@58.75,-2.75 62.95,-2.75 65.8,-5.6 80.8,-5.6 87.5,-12.3 109.05,-12.3 110.7,-13.95 v1(110.7,-14.8)
  Bottom Layer w0.12: P10.27@110.6,-13.85 110.6,-14.7 v1(110.7,-14.8)
ECLK22N: IC1.B17 P9.28 pad.1@60.25,3.25 | length 54.5
  Top Layer w0.13: IC1.B17@60,3.5 pad.1@60.25,3.25
  M2 w0.12: pad.1@60.25,3.25 60.3,3.25 64.15,3.25 68.3,7.4 76,7.4 82.1,13.5 107.6,13.5 108.3,14.2 v1(108.3,14.8)
  Bottom Layer w0.12: P9.28@108.2,13.85 108.2,14.7 v1(108.3,14.8)
ECLK22P: IC1.B16 P9.27 pad.1@59.75,3.25 | length 54.5
  Top Layer w0.13: IC1.B16@59.5,3.5 pad.1@59.75,3.25
  M2 w0.12: pad.1@59.75,3.25 60.2,3.7 63.6,3.7 67.9,8 75.4,8 81.5,14.1 103,14.1 103.5,14.6 105.2,14.6 105.7,14.1 107,14.1 v1(107.7,14.8)
  Bottom Layer w0.12: v1(107.7,14.8) 107.8,14.7 P9.27@107.8,13.85
ECLK23N: IC1.A17 P7.40 pad.1@60.25,4.25 | length 17.7
  Top Layer w0.13: IC1.A17@60,4 pad.1@60.25,4.25
  M2 w0.12: pad.1@60.25,4.25 60.8,4.8 60.8,7 62.8,9 62.8,10.5 65.6,13.3 68.9,13.3 69.5,13.9 v1(69.5,14.8)
  Bottom Layer w0.12: P7.40@69.4,13.85 69.4,14.7 v1(69.5,14.8)
ECLK23P: IC1.A16 P7.39 pad.1@59.75,4.25 | length 17.7
  Top Layer w0.13: IC1.A16@59.5,4 pad.1@59.75,4.25
  M2 w0.12: pad.1@59.75,4.25 59.75,6.85 62,9.1 62,10.8 65.2,14 68.6,14 68.9,14.3 v1(68.9,14.8)
  Bottom Layer w0.12: v1(68.9,14.8) 69,14.7 P7.39@69,13.85
ECLK24N: IC1.C15 P9.39 pad.1@59.25,2.75 | length 61.5
  Top Layer w0.13: IC1.C15@59,3 pad.1@59.25,2.75
  M2 w0.12: pad.1@59.25,2.75 66.15,2.75 69.9,6.5 70.5,6.5 71.2,5.8 72.5,5.8 73.2,6.5 74,6.5 74.8,5.7 75.6,5.7 82.7,12.8 108.3,12.8 108.6,13.1 109.2,13.1 109.6,12.7 110.9,12.7 112.5,14.3 v1(112.5,14.8)
  Bottom Layer w0.12: v1(112.5,14.8) 112.6,14.7 P9.39@112.6,13.85
ECLK24P: IC1.C14 P9.40 pad.1@58.75,2.75 | length 61.4
  Top Layer w0.13: IC1.C14@58.5,3 pad.1@58.75,2.75
  M2 w0.12: pad.1@58.75,2.75 59.2,2.3 66.7,2.3 69.4,5 76.1,5 83.3,12.2 111.1,12.2 113.1,14.2 v1(113.1,14.8)
  Bottom Layer w0.12: P9.40@113,13.85 113,14.7 v1(113.1,14.8)
ECLK25N: IC1.A15 P7.28 pad.1@58.752,4.25 | length 17.6
  Top Layer w0.13: pad.1@58.752,4.25 IC1.A15@59,4
  M2 w0.12: pad.1@58.752,4.25 58.75,4.252 58.75,4.95 58.3,5.4 58.3,6.9 58.8,7.4 58.8,9.1 58.3,9.6 58.3,11.4 60.1,13.2 60.7,13.2 61.3,12.6 61.9,12.6 62.5,13.2 63.5,13.2 64.7,14.4 v1(64.7,14.8)
  Bottom Layer w0.12: P7.28@64.6,13.85 64.6,14.7 v1(64.7,14.8)
ECLK25P: IC1.B15 P7.27 pad.1@58.75,3.75 | length 17.7
  Top Layer w0.13: pad.1@58.75,3.75 IC1.B15@59,3.5
  M2 w0.12: pad.1@58.75,3.75 57.6,4.9 57.6,11.9 59.8,14.1 63.4,14.1 v1(64.1,14.8)
  Bottom Layer w0.12: v1(64.1,14.8) 64.2,14.7 P7.27@64.2,13.85
ECLK26N: IC1.C5 P5.40 pad.1@54.25,3.25 | length 36.4
  Top Layer w0.13: IC1.C5@54,3 pad.1@54.25,3.25
  M2 w0.12: v1(25.9,14.8) 26.4,14.3 46.4,14.3 54.25,6.45 pad.1@54.25,3.25
  Bottom Layer w0.12: P5.40@25.8,13.85 25.8,14.7 v1(25.9,14.8)
ECLK26P: IC1.D5 P5.39 pad.1@53.75,2.75 | length 36.4
  Top Layer w0.13: pad.1@53.75,2.75 IC1.D5@54,2.5
  M2 w0.12: v1(25.3,14.8) 25.3,14.1 25.6,13.8 44.7,13.8 53.75,4.75 pad.1@53.75,2.75
  Bottom Layer w0.12: v1(25.3,14.8) 25.4,14.7 P5.39@25.4,13.85
ECLK27N: IC1.C4 P5.28 pad.1@53.25,3.25 | length 40
  Top Layer w0.13: pad.1@53.25,3.25 IC1.C4@53.5,3
  M2 w0.12: v1(21.1,14.8) 21.1,14.2 22,13.3 35.2,13.3 36.7,11.8 38.3,11.8 38.9,12.4 40.35,12.4 40.95,11.8 42.3,11.8 42.9,12.4 44.8,12.4 53.25,3.95 pad.1@53.25,3.25
  Bottom Layer w0.12: P5.28@21,13.85 21,14.7 v1(21.1,14.8)
ECLK27P: IC1.D4 P5.27 pad.1@53.25,2.25 | length 40
  Top Layer w0.13: pad.1@53.25,2.25 IC1.D4@53.5,2.5
  M2 w0.12: v1(20.5,14.8) 20.5,13.7 21.4,12.8 34.2,12.8 37.9,9.1 41.1,9.1 42.196,8.004 47.804,8.004 pad.1@53.25,2.25
  Bottom Layer w0.12: v1(20.5,14.8) 20.6,14.7 P5.27@20.6,13.85
EDIN00N: IC1.U5 P6.34 | length 43
  Top Layer w0.12: v1(20.5,-14.8) 20.5,-14.2 22.1,-12.6 25.3,-12.6 25.8,-12.1 27.2,-12.1 27.7,-12.6 28.5,-12.6 30.5,-10.6 53,-10.6 53.75,-9.85 53.75,-4.75 54,-4.5 IC1.U5@54,-4
  Bottom Layer w0.12: v1(20.5,-14.8) 20.6,-14.7 P6.34@20.6,-13.85
EDIN00P: IC1.T5 P6.33 | length 43.1
  Top Layer w0.076: IC1.T5@54,-3.5 54.25,-3.75 54.25,-4.25
  Top Layer w0.12: v1(21.1,-14.8) 21.1,-14.6 22.4,-13.3 29.2,-13.3 30.675,-11.825 52.775,-11.825 54.25,-10.35 54.25,-4.25
  Bottom Layer w0.12: P6.33@21,-13.85 21,-14.7 v1(21.1,-14.8)
EDIN02N: IC1.U7 P6.25 | length 40.9
  Top Layer w0.12: v1(24.1,-14.464) 24.1,-14.3 24.4,-14 30.5,-14 31.1,-13.4 32.8,-13.4 33.4,-14 34.8,-14 35.4,-13.4 36.9,-13.4 37.5,-14 51.6,-14 54.75,-10.85 54.75,-4.25 IC1.U7@55,-4
  Bottom Layer w0.12: v1(24.1,-14.464) 24.2,-14.464 P6.25@24.2,-13.85
EDIN02P: IC1.T7 P6.24 | length 40.9
  Top Layer w0.076: IC1.T7@55,-3.5 55.25,-3.75 55.25,-4.25
  Top Layer w0.12: v1(24.7,-14.464) 24.7,-14.6 24.9,-14.8 51.8,-14.8 55.25,-11.35 55.25,-4.25
  Bottom Layer w0.12: P6.24@24.6,-13.85 24.6,-14.464 v1(24.7,-14.464)
EDIN10N: IC1.U11 P8.34 | length 18.5
  Top Layer w0.12: IC1.U11@57,-4 57,-4.6 56.5,-5.1 56.5,-12.6 57.8,-13.9 63.6,-13.9 64.1,-14.4 v1(64.1,-14.8)
  Bottom Layer w0.12: v1(64.1,-14.8) 64.2,-14.7 P8.34@64.2,-13.85
EDIN10P: IC1.T11 P8.33 | length 18.6
  Top Layer w0.076: IC1.T11@57,-3.5 57.25,-3.75 57.25,-4.25
  Top Layer w0.12: 57.25,-4.25 57.25,-5 57,-5.25 57,-11.3 59,-13.3 63.9,-13.3 64.7,-14.1 v1(64.7,-14.8)
  Bottom Layer w0.12: P8.33@64.6,-13.85 64.6,-14.7 v1(64.7,-14.8)
EDIN12N: IC1.U13 P8.24 | length 20.7
  Top Layer w0.12: IC1.U13@58,-4 58,-10.75 59.25,-12 60.2,-12 60.8,-11.4 61.7,-11.4 62.3,-12 66.4,-12 68.3,-13.9 v1(68.3,-14.8)
  Bottom Layer w0.12: P8.24@68.2,-13.85 68.2,-14.7 v1(68.3,-14.8)
EDIN12P: IC1.T13 P8.25 | length 20.7
  Top Layer w0.076: 57.75,-4.25 57.75,-3.75 IC1.T13@58,-3.5
  Top Layer w0.12: 57.75,-4.25 57.75,-5.25 57.5,-5.5 57.5,-11 59.1,-12.6 65.9,-12.6 67.7,-14.4 v1(67.7,-14.8)
  Bottom Layer w0.12: v1(67.7,-14.8) 67.8,-14.7 P8.25@67.8,-13.85
EDIN20N: IC1.P17 P10.34 | length 55.4
  Top Layer w0.12: IC1.P17@60,-2.5 60.25,-2.75 60.75,-2.75 65.25,-7.25 72.75,-7.25 79.75,-14.25 85.55,-14.25 86.9,-15.6 88.4,-15.6 88.8,-15.2 90.6,-15.2 91,-15.6 93,-15.6 93.5,-15.1 94.9,-15.1 95.4,-15.6 107.3,-15.6 107.7,-15.2 v1(107.7,-14.8)
  Bottom Layer w0.12: v1(107.7,-14.8) 107.8,-14.7 P10.34@107.8,-13.85
EDIN20P: IC1.P16 P10.33 | length 55.4
  Top Layer w0.076: IC1.P16@59.5,-2.5 59.75,-2.25 60.25,-2.25
  Top Layer w0.12: 60.25,-2.25 61,-2.25 65.5,-6.75 73.5,-6.75 80.25,-13.5 86.9,-13.5 87.5,-14.1 108.1,-14.1 108.3,-14.3 v1(108.3,-14.8)
  Bottom Layer w0.12: P10.33@108.2,-13.85 108.2,-14.7 v1(108.3,-14.8)
EDIN22N: IC1.M17 P10.25 | length 59.7
  Top Layer w0.12: IC1.M17@60,-1.5 60.25,-1.75 61.25,-1.75 65.75,-6.25 74.25,-6.25 80.7,-12.7 89.4,-12.7 89.9,-13.2 91.4,-13.2 91.9,-12.7 93.5,-12.7 94,-13.2 95.3,-13.2 95.8,-12.7 96.9,-12.7 97.4,-13.2 98.5,-13.2 99,-12.7 100.1,-12.7 100.5,-13.1 101.8,-13.1 102.2,-12.7 109.7,-12.7 111.3,-14.3 v1(111.3,-14.8)
  Bottom Layer w0.12: v1(111.3,-14.8) 111.4,-14.7 P10.25@111.4,-13.85
EDIN22P: IC1.M16 P10.24 | length 59.6
  Top Layer w0.076: IC1.M16@59.5,-1.5 59.75,-1.25 60.25,-1.25
  Top Layer w0.12: 60.25,-1.25 61.5,-1.25 66,-5.75 75,-5.75 81.25,-12 110,-12 111.9,-13.9 v1(111.9,-14.8)
  Bottom Layer w0.12: P10.24@111.8,-13.85 111.8,-14.7 v1(111.9,-14.8)
EDIN30N: IC1.H17 P9.34 | length 59.3
  Top Layer w0.12: IC1.H17@60,0.5 61.3,0.5 62.4,1.6 62.4,3.6 66.3,7.5 75.5,7.5 80.6,12.6 109.3,12.6 110.7,14 v1(110.7,14.8)
  Bottom Layer w0.12: P9.34@110.6,13.85 110.6,14.7 v1(110.7,14.8)
EDIN30P: IC1.H16 P9.33 | length 59.3
  Top Layer w0.076: IC1.H16@59.5,0.5 59.75,0.75 60.25,0.75
  Top Layer w0.12: 60.25,0.75 60.5,1 60.9,1 61.8,1.9 61.8,4.5 65.3,8 74.2,8 79.5,13.3 109,13.3 110.1,14.4 v1(110.1,14.8)
  Bottom Layer w0.12: v1(110.1,14.8) 110.2,14.7 P9.33@110.2,13.85
EDIN32N: IC1.F17 P9.25 | length 55.7
  Top Layer w0.12: IC1.F17@60,1.5 60.7,1.5 61.3,2.1 61.3,5.1 64.7,8.5 72.9,8.5 78.4,14 106.8,14 107.1,14.3 v1(107.1,14.8)
  Bottom Layer w0.12: P9.25@107,13.85 107,14.7 v1(107.1,14.8)
EDIN32P: IC1.F16 P9.24 | length 55.7
  Top Layer w0.076: IC1.F16@59.5,1.5 59.75,1.75 60.25,1.75
  Top Layer w0.12: 60.25,1.75 60.8,2.3 60.8,6 63.8,9 71.9,9 77.7,14.8 v1(106.5,14.8)
  Bottom Layer w0.12: v1(106.5,14.8) 106.6,14.7 P9.24@106.6,13.85
EDIN40N: IC1.A14 P7.34 | length 16.7
  Top Layer w0.076: IC1.A14@58.5,4 58.5,4.75
  Top Layer w0.12: 58.5,4.75 62.6,8.85 62.6,11.3 64.3,13 66.6,13 67.1,13.5 v1(67.1,14.8)
  Bottom Layer w0.12: P7.34@67,13.85 67,14.7 v1(67.1,14.8)
EDIN40P: IC1.B14 P7.33 | length 16.7
  Top Layer w0.076: 58.25,4.2 58.25,3.75 IC1.B14@58.5,3.5
  Top Layer w0.12: 58.25,4.2 58,4.45 58,5.25 61.9,9.15 61.9,11.4 64.3,13.8 65.5,13.8 v1(66.5,14.8)
  Bottom Layer w0.12: v1(66.5,14.8) 66.6,14.7 P7.33@66.6,13.85
EDIN42N: IC1.A12 P7.25 | length 16.3
  Top Layer w0.12: IC1.A12@57.5,4 57.5,6.6 58.2,7.3 58.2,8.6 57.5,9.3 57.5,10.75 59.95,13.2 62.4,13.2 63.5,14.3 v1(63.5,14.8)
  Bottom Layer w0.12: P7.25@63.4,13.85 63.4,14.7 v1(63.5,14.8)
EDIN42P: IC1.B12 P7.24 | length 16.3
  Top Layer w0.076: 57.25,4.2 57.25,3.75 IC1.B12@57.5,3.5
  Top Layer w0.12: 57.25,4.2 57,4.45 57,11.25 59.85,14.1 62.2,14.1 v1(62.9,14.8)
  Bottom Layer w0.12: v1(62.9,14.8) 63,14.7 P7.24@63,13.85
EDIN50N: IC1.A10 P5.34 | length 40.6
  Top Layer w0.12: v1(23.5,14.8) 24.2,15.5 47.6,15.5 56.5,6.6 IC1.A10@56.5,4
  Bottom Layer w0.12: P5.34@23.4,13.85 23.4,14.7 v1(23.5,14.8)
EDIN50P: IC1.B10 P5.33 | length 40.6
  Top Layer w0.076: 56.25,4.25 56.25,3.75 IC1.B10@56.5,3.5
  Top Layer w0.12: v1(22.9,14.8) 22.9,14.4 23.2,14.1 47.7,14.1 56,5.8 56,4.5 56.25,4.25
  Bottom Layer w0.12: v1(22.9,14.8) 23,14.7 P5.33@23,13.85
EDIN52N: IC1.A8 P5.25 | length 42.4
  Top Layer w0.12: v1(19.9,14.8) 19.9,15.1 20.2,15.4 21.3,15.4 23.2,13.5 47.1,13.5 55.5,5.1 IC1.A8@55.5,4
  Bottom Layer w0.12: P5.25@19.8,13.85 19.8,14.7 v1(19.9,14.8)
EDIN52P: IC1.B8 P5.24 | length 42.4
  Top Layer w0.076: 55.25,4.25 55.25,3.75 IC1.B8@55.5,3.5
  Top Layer w0.12: v1(19.3,14.8) 19.3,14.4 20.8,12.9 46.6,12.9 55.25,4.25
  Bottom Layer w0.12: v1(19.3,14.8) 19.4,14.7 P5.24@19.4,13.85
EDOUT00N: IC1.R5 P6.36 pad.1@54.25,-3.25 | length 41.8
  Top Layer w0.13: IC1.R5@54,-3 pad.1@54.25,-3.25
  M1 w0.12: v1(19.9,-14.8) 19.9,-14.2 20.3,-13.8 28.6,-13.8 29,-14.2 29.8,-14.2 30.2,-13.8 39.9,-13.8 48.9,-4.8 53.75,-4.8 54.25,-4.3 pad.1@54.25,-3.25
  Bottom Layer w0.12: P6.36@19.8,-13.85 19.8,-14.7 v1(19.9,-14.8)
EDOUT00P: IC1.P5 P6.37 pad.1@54.25,-2.75 | length 41.8
  Top Layer w0.13: IC1.P5@54,-2.5 pad.1@54.25,-2.75
  M1 w0.12: v1(19.3,-14.8) 19.3,-13.95 20.25,-13 39.75,-13 48.75,-4 53,-4 pad.1@54.25,-2.75
  Bottom Layer w0.12: v1(19.3,-14.8) 19.4,-14.7 P6.37@19.4,-13.85
EDOUT02N: IC1.R7 P8.37 pad.1@55.25,-3.25 | length 16.8
  Top Layer w0.13: IC1.R7@55,-3 pad.1@55.25,-3.25
  M1 w0.13: pad.1@55.25,-3.25 55.25,-8.4 61.05,-14.2 62.3,-14.2 v1(62.9,-14.8)
  Bottom Layer w0.12: v1(62.9,-14.8) 63,-14.7 P8.37@63,-13.85
EDOUT02P: IC1.P7 P8.36 pad.1@55.25,-2.75 | length 16.8
  Top Layer w0.13: IC1.P7@55,-2.5 pad.1@55.25,-2.75
  M1 w0.12: pad.1@55.25,-2.75 56.15,-3.65 56.15,-7 62.7,-13.55 63.5,-14.35 v1(63.5,-14.8)
  Bottom Layer w0.12: P8.36@63.4,-13.85 63.4,-14.7 v1(63.5,-14.8)
EDOUT10N: IC1.R9 P10.37 pad.1@56.25,-3.25 | length 57.9
  Top Layer w0.13: IC1.R9@56,-3 pad.1@56.25,-3.25
  M1 w0.12: pad.1@56.25,-3.25 56.75,-3.25 57.25,-3.75 57.25,-4.75 61,-8.5 74.25,-8.5 79.95,-14.2 101.5,-14.2 102.4,-15.1 103.4,-15.1 104.3,-14.2 106.2,-14.2 106.5,-14.5 v1(106.5,-14.8)
  Bottom Layer w0.12: v1(106.5,-14.8) 106.6,-14.7 P10.37@106.6,-13.85
EDOUT10P: IC1.P9 P10.36 pad.1@56.25,-2.75 | length 57.9
  Top Layer w0.13: IC1.P9@56,-2.5 pad.1@56.25,-2.75
  M1 w0.12: pad.1@56.25,-2.75 56.75,-2.75 57.75,-3.75 57.75,-4.25 61.5,-8 74.75,-8 80.25,-13.5 106.5,-13.5 107.1,-14.1 v1(107.1,-14.8)
  Bottom Layer w0.12: P10.36@107,-13.85 107,-14.7 v1(107.1,-14.8)
EDOUT20N: IC1.C13 P9.37 pad.1@57.75,3.25 | length 61.8
  Top Layer w0.13: pad.1@57.75,3.25 IC1.C13@58,3
  M1 w0.12: pad.1@57.75,3.25 57.75,4.45 60.8,7.5 74.3,7.5 80.1,13.3 103.6,13.3 104.2,12.7 106.1,12.7 106.7,13.3 111,13.3 111.9,14.2 v1(111.9,14.8)
  Bottom Layer w0.12: P9.37@111.8,13.85 111.8,14.7 v1(111.9,14.8)
EDOUT20P: IC1.D13 P9.36 pad.1@57.75,2.75 | length 61.8
  Top Layer w0.13: pad.1@57.75,2.75 IC1.D13@58,2.5
  M1 w0.12: pad.1@57.75,2.75 57.25,3.25 57.25,4.85 60.4,8 73.8,8 79.9,14.1 110.6,14.1 v1(111.3,14.8)
  Bottom Layer w0.12: v1(111.3,14.8) 111.4,14.7 P9.36@111.4,13.85
EDOUT22N: IC1.C11 P7.37 pad.1@56.75,3.25 | length 22.5
  Top Layer w0.13: pad.1@56.75,3.25 IC1.C11@57,3
  M1 w0.12: pad.1@56.75,3.25 56.75,9.85 60,13.1 61.3,13.1 61.9,12.5 63.7,12.5 64.3,13.1 67.3,13.1 68.3,14.1 v1(68.3,14.8)
  Bottom Layer w0.12: P7.37@68.2,13.85 68.2,14.7 v1(68.3,14.8)
EDOUT22P: IC1.D11 P7.36 pad.1@56.75,2.75 | length 22.4
  Top Layer w0.13: pad.1@56.75,2.75 IC1.D11@57,2.5
  M1 w0.12: pad.1@56.75,2.75 56.25,3.25 56.25,10.35 59.8,13.9 66.8,13.9 v1(67.7,14.8)
  Bottom Layer w0.12: v1(67.7,14.8) 67.8,14.7 P7.36@67.8,13.85
EDOUT30N: IC1.C9 P5.37 pad.1@55.75,3.25 | length 38.2
  Top Layer w0.13: pad.1@55.75,3.25 IC1.C9@56,3
  M1 w0.12: v1(24.7,14.8) 25.4,15.5 26.7,15.5 28.4,13.8 45.9,13.8 55.75,3.95 pad.1@55.75,3.25
  Bottom Layer w0.12: P5.37@24.6,13.85 24.6,14.7 v1(24.7,14.8)
EDOUT30P: IC1.D9 P5.36 pad.1@55.75,2.75 | length 38.2
  Top Layer w0.13: pad.1@55.75,2.75 IC1.D9@56,2.5
  M1 w0.12: v1(24.1,14.8) 24.1,14.5 25.5,13.1 45.4,13.1 pad.1@55.75,2.75
  Bottom Layer w0.12: v1(24.1,14.8) 24.2,14.7 P5.36@24.2,13.85
GBT_RESET_B: IC1.N13 IC3.M14 R107.2 | length 46.6
  Top Layer w0.076: IC1.N13@58,-2 58.25,-2.25 58.25,-4.25
  Top Layer w0.102: 58.25,-4.25 62.3,-8.3 72.3,-8.3 79,-15 84.8,-15 v1(84.8,-15.036) ; v1(82.8,-10.2) 82.8,-9.6 IC3.M14@87.2,-5.2
  Bottom Layer w0.102: R107.2@82.8,-9.5 v1(82.8,-10.2) 84.8,-12.2 v1(84.8,-15.036)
